One B-rep face of a CAD part: STEP entity #56574.
In plain terms, the planar face has unit normal (0, 0, 1).
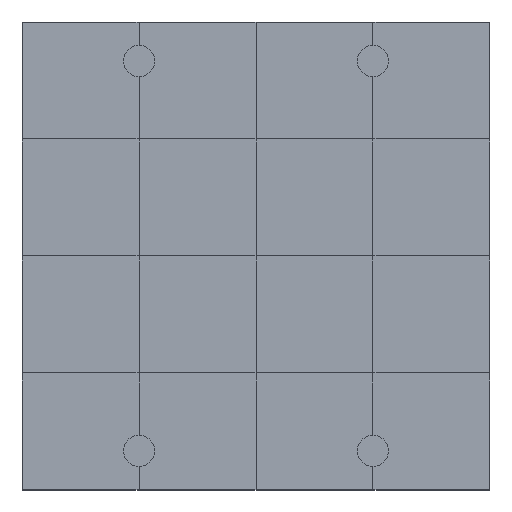
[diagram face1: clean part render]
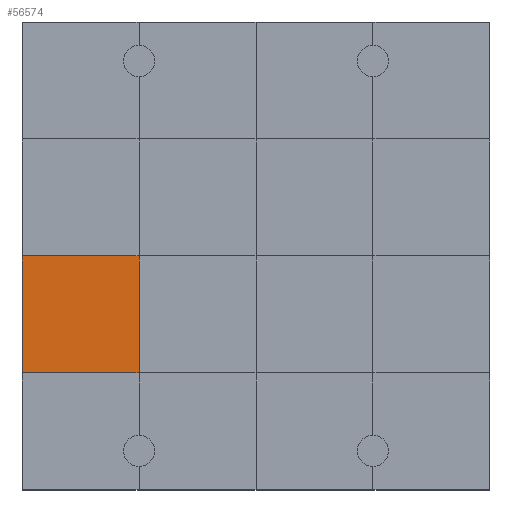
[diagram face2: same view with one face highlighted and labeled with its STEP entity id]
Its self-contained STEP definition (entity closure, numbers rounded to 3 decimals):
#56124 = VERTEX_POINT('',#56125);
#56125 = CARTESIAN_POINT('',(0.,3.,1.2));
#56139 = PLANE('',#56140);
#56140 = AXIS2_PLACEMENT_3D('',#56141,#56142,#56143);
#56141 = CARTESIAN_POINT('',(0.,3.,0.));
#56142 = DIRECTION('',(1.,0.,-0.));
#56143 = DIRECTION('',(0.,0.,1.));
#56165 = PLANE('',#56166);
#56166 = AXIS2_PLACEMENT_3D('',#56167,#56168,#56169);
#56167 = CARTESIAN_POINT('',(0.,0.,1.2));
#56168 = DIRECTION('',(0.,0.,1.));
#56169 = DIRECTION('',(1.,0.,-0.));
#56316 = VERTEX_POINT('',#56317);
#56317 = CARTESIAN_POINT('',(3.,3.,1.2));
#56338 = EDGE_CURVE('',#56124,#56316,#56339,.T.);
#56339 = SURFACE_CURVE('',#56340,(#56344,#56351),.PCURVE_S1.);
#56340 = LINE('',#56341,#56342);
#56341 = CARTESIAN_POINT('',(0.,3.,1.2));
#56342 = VECTOR('',#56343,1.);
#56343 = DIRECTION('',(1.,0.,-0.));
#56344 = PCURVE('',#56165,#56345);
#56345 = DEFINITIONAL_REPRESENTATION('',(#56346),#56350);
#56346 = LINE('',#56347,#56348);
#56347 = CARTESIAN_POINT('',(0.,3.));
#56348 = VECTOR('',#56349,1.);
#56349 = DIRECTION('',(1.,0.));
#56350 = ( GEOMETRIC_REPRESENTATION_CONTEXT(2) 
PARAMETRIC_REPRESENTATION_CONTEXT() REPRESENTATION_CONTEXT('2D SPACE',''
  ) );
#56351 = PCURVE('',#56352,#56357);
#56352 = PLANE('',#56353);
#56353 = AXIS2_PLACEMENT_3D('',#56354,#56355,#56356);
#56354 = CARTESIAN_POINT('',(0.,3.,1.2));
#56355 = DIRECTION('',(0.,0.,1.));
#56356 = DIRECTION('',(1.,0.,-0.));
#56357 = DEFINITIONAL_REPRESENTATION('',(#56358),#56362);
#56358 = LINE('',#56359,#56360);
#56359 = CARTESIAN_POINT('',(0.,0.));
#56360 = VECTOR('',#56361,1.);
#56361 = DIRECTION('',(1.,0.));
#56362 = ( GEOMETRIC_REPRESENTATION_CONTEXT(2) 
PARAMETRIC_REPRESENTATION_CONTEXT() REPRESENTATION_CONTEXT('2D SPACE',''
  ) );
#56397 = VERTEX_POINT('',#56398);
#56398 = CARTESIAN_POINT('',(0.,6.,1.2));
#56424 = EDGE_CURVE('',#56124,#56397,#56425,.T.);
#56425 = SURFACE_CURVE('',#56426,(#56430,#56437),.PCURVE_S1.);
#56426 = LINE('',#56427,#56428);
#56427 = CARTESIAN_POINT('',(0.,3.,1.2));
#56428 = VECTOR('',#56429,1.);
#56429 = DIRECTION('',(-0.,1.,0.));
#56430 = PCURVE('',#56139,#56431);
#56431 = DEFINITIONAL_REPRESENTATION('',(#56432),#56436);
#56432 = LINE('',#56433,#56434);
#56433 = CARTESIAN_POINT('',(1.2,0.));
#56434 = VECTOR('',#56435,1.);
#56435 = DIRECTION('',(0.,-1.));
#56436 = ( GEOMETRIC_REPRESENTATION_CONTEXT(2) 
PARAMETRIC_REPRESENTATION_CONTEXT() REPRESENTATION_CONTEXT('2D SPACE',''
  ) );
#56437 = PCURVE('',#56352,#56438);
#56438 = DEFINITIONAL_REPRESENTATION('',(#56439),#56443);
#56439 = LINE('',#56440,#56441);
#56440 = CARTESIAN_POINT('',(0.,0.));
#56441 = VECTOR('',#56442,1.);
#56442 = DIRECTION('',(0.,1.));
#56443 = ( GEOMETRIC_REPRESENTATION_CONTEXT(2) 
PARAMETRIC_REPRESENTATION_CONTEXT() REPRESENTATION_CONTEXT('2D SPACE',''
  ) );
#56574 = ADVANCED_FACE('',(#56575),#56352,.T.);
#56575 = FACE_BOUND('',#56576,.T.);
#56576 = EDGE_LOOP('',(#56577,#56578,#56579,#56607));
#56577 = ORIENTED_EDGE('',*,*,#56424,.F.);
#56578 = ORIENTED_EDGE('',*,*,#56338,.T.);
#56579 = ORIENTED_EDGE('',*,*,#56580,.T.);
#56580 = EDGE_CURVE('',#56316,#56581,#56583,.T.);
#56581 = VERTEX_POINT('',#56582);
#56582 = CARTESIAN_POINT('',(3.,6.,1.2));
#56583 = SURFACE_CURVE('',#56584,(#56588,#56595),.PCURVE_S1.);
#56584 = LINE('',#56585,#56586);
#56585 = CARTESIAN_POINT('',(3.,3.,1.2));
#56586 = VECTOR('',#56587,1.);
#56587 = DIRECTION('',(-0.,1.,0.));
#56588 = PCURVE('',#56352,#56589);
#56589 = DEFINITIONAL_REPRESENTATION('',(#56590),#56594);
#56590 = LINE('',#56591,#56592);
#56591 = CARTESIAN_POINT('',(3.,0.));
#56592 = VECTOR('',#56593,1.);
#56593 = DIRECTION('',(0.,1.));
#56594 = ( GEOMETRIC_REPRESENTATION_CONTEXT(2) 
PARAMETRIC_REPRESENTATION_CONTEXT() REPRESENTATION_CONTEXT('2D SPACE',''
  ) );
#56595 = PCURVE('',#56596,#56601);
#56596 = PLANE('',#56597);
#56597 = AXIS2_PLACEMENT_3D('',#56598,#56599,#56600);
#56598 = CARTESIAN_POINT('',(3.,3.,1.2));
#56599 = DIRECTION('',(0.,0.,1.));
#56600 = DIRECTION('',(1.,0.,-0.));
#56601 = DEFINITIONAL_REPRESENTATION('',(#56602),#56606);
#56602 = LINE('',#56603,#56604);
#56603 = CARTESIAN_POINT('',(0.,0.));
#56604 = VECTOR('',#56605,1.);
#56605 = DIRECTION('',(0.,1.));
#56606 = ( GEOMETRIC_REPRESENTATION_CONTEXT(2) 
PARAMETRIC_REPRESENTATION_CONTEXT() REPRESENTATION_CONTEXT('2D SPACE',''
  ) );
#56607 = ORIENTED_EDGE('',*,*,#56608,.F.);
#56608 = EDGE_CURVE('',#56397,#56581,#56609,.T.);
#56609 = SURFACE_CURVE('',#56610,(#56614,#56621),.PCURVE_S1.);
#56610 = LINE('',#56611,#56612);
#56611 = CARTESIAN_POINT('',(0.,6.,1.2));
#56612 = VECTOR('',#56613,1.);
#56613 = DIRECTION('',(1.,0.,-0.));
#56614 = PCURVE('',#56352,#56615);
#56615 = DEFINITIONAL_REPRESENTATION('',(#56616),#56620);
#56616 = LINE('',#56617,#56618);
#56617 = CARTESIAN_POINT('',(0.,3.));
#56618 = VECTOR('',#56619,1.);
#56619 = DIRECTION('',(1.,0.));
#56620 = ( GEOMETRIC_REPRESENTATION_CONTEXT(2) 
PARAMETRIC_REPRESENTATION_CONTEXT() REPRESENTATION_CONTEXT('2D SPACE',''
  ) );
#56621 = PCURVE('',#56622,#56627);
#56622 = PLANE('',#56623);
#56623 = AXIS2_PLACEMENT_3D('',#56624,#56625,#56626);
#56624 = CARTESIAN_POINT('',(0.,6.,1.2));
#56625 = DIRECTION('',(0.,0.,1.));
#56626 = DIRECTION('',(1.,0.,-0.));
#56627 = DEFINITIONAL_REPRESENTATION('',(#56628),#56632);
#56628 = LINE('',#56629,#56630);
#56629 = CARTESIAN_POINT('',(0.,0.));
#56630 = VECTOR('',#56631,1.);
#56631 = DIRECTION('',(1.,0.));
#56632 = ( GEOMETRIC_REPRESENTATION_CONTEXT(2) 
PARAMETRIC_REPRESENTATION_CONTEXT() REPRESENTATION_CONTEXT('2D SPACE',''
  ) );
